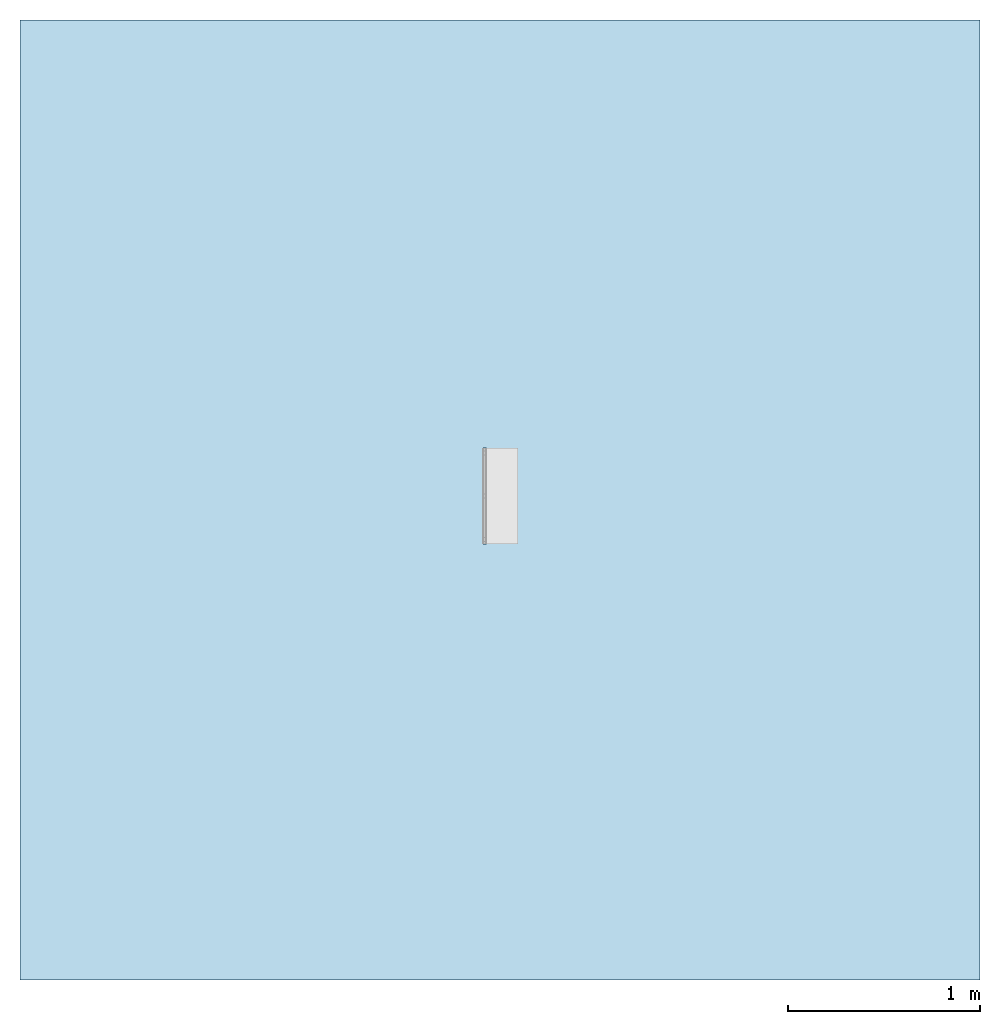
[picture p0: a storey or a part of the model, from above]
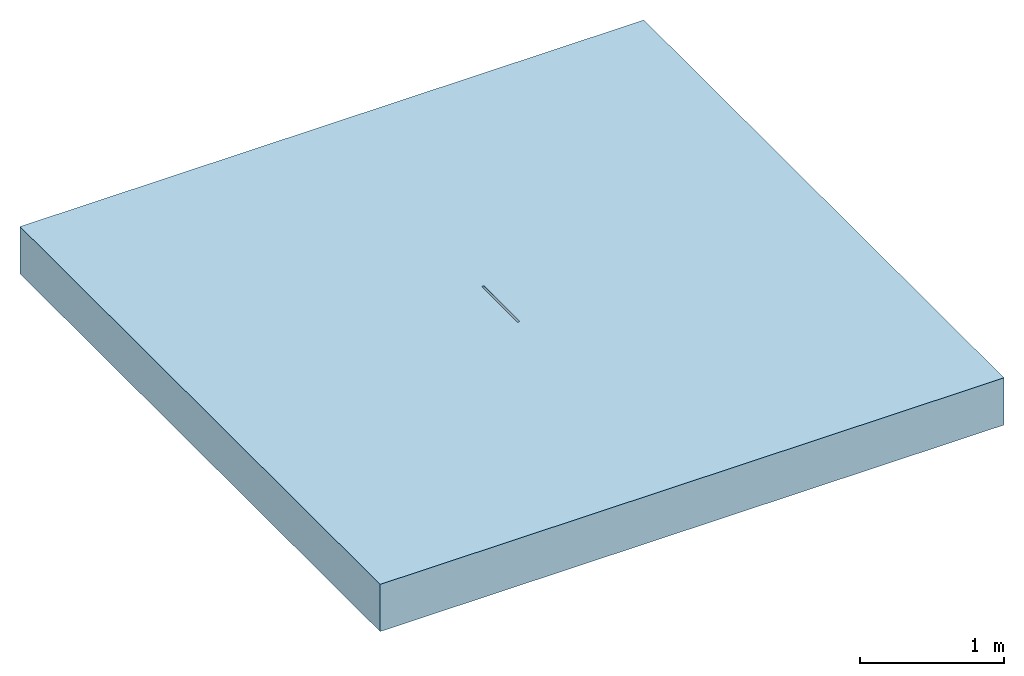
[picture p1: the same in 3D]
Properties of the parts of a building model (IFC2X3)

# File
Description: ViewDefinition [CoordinationView]
File name: 23153 - No 0.1J Constant Depth Channel - 500mm LG - Invert Depth 185mm.ifc
Time: 2013-10-30T12:23:05
Written by: Autodesk Revit 2013
Made in: 20120221_2030(x64)

# IfcProject, Project Number
LongName: Project Name; Phase: Project Status

# IfcSite, Default
RefLatitude: 42, 21, 30, 344238; RefLongitude: -71, -3, -35, -194702; RefElevation: 0 mm

# IfcBuilding
Pset_BuildingCommon - NumberOfStoreys: 1
Other - Project Address: ## Street City, State Zip; Project Issue Date: Issue Date; Project Name: Project Name; Project Number: Project Number; Client Name: Owner; Project Status: Project Status

# IfcBuildingStorey, Level 1
LongName: Level 1; Elevation: 0 mm
Constraints - Elevation Base: 0; Elevation: 0 mm
Graphics - Color: 0; Symbol at End 2 Default: yes; Line Pattern: Center; Symbol at End 1 Default: no; Line Weight: 1; Symbol: M_Level Head - Circle: M_Level Head - Circle
Identity Data - Name: Level 1; Structural: no; Building Story: yes
Dimensions - Computation Height: 0 mm

# IfcBuildingElementProxy: 23153 - No 0.1J Constant Depth Channel - 500mm LG - Invert Depth 185mm, Civil-Drainage-Channel-ACO-MultiDrain-M150D-Brickslot-Channel-System:23153 - No 0.1J Constant Depth Channel - 500mm LG - Invert Depth 185mm:23153 - No 0.1J Constant Depth Channel - 500mm LG - Invert Depth 185mm:196059
In: Level 1
Material: Steel, Galvanized, Vienite® Synthetic Resin Concrete
Dimensions - EndCap Position: 500 mm; FloorCut_Length: -500 mm; Custom_Void_Length: 0 mm; Volume: 6289628 mm3; Brickslot Access Unit Void Depth: -6000 mm; Length: 1000 mm; Brickslot Grating Void Depth: 0 mm; Brickslot Void Length: -500 mm; Brickslot Access Unit Void Bottom Depth: -6105 mm; Floor cut gap depth for access unit: 105 mm; EndCap_Height: -210 mm; Length Drain: -500 mm; Depth: 210 mm; InvDepth: 110 mm; End Cap Thickess: 3 mm; Floor Cut Gap: 105 mm; FloorCut_Width: 185 mm; FloorCut_HorPosition: 92.5 mm; FloorCut_Depth: 210 mm
Constraints - Level: Level: Level 1; Moves With Nearby Elements: no
Construction - 23159_Universal Endcap (Male End): no; 23175_Load Class C250 & D400_Brickslot Grating_Galvanized Steel_1000mm Long: no; 23159_Universal Endcap (Female End): no; 23177_Load Class C250 & D400_Brickslot_Access Unit_Galvanized Steel_500mm Long: no; 23176_Load Class C250 & D400_Brickslot Grating_Galvanized Steel_500mm Long: yes; Constant Depth Channel_1000: no; 23157_Shallow Depth Channel with seal: no; Constant Depth Channel_500: yes; Sump Unit: no; 23156_Shallow Depth Channel: no
Phasing - Phase Created: New Construction
Pset_BuildingElementProxyCommon - Reference: 23153 - No 0.1J Constant Depth Channel - 500mm LG - Invert Depth 185mm
Identity Data - Product Code: 23153; Address: ACO Business Park, Hitchin Road, Shefford, Bedfordshire, United Kingdom SG17 5TE; Manufacturer: ACO Technologies plc - ACO Water Management Division; Watermark 2: This file is water marked and users are prohibited to reproduce, adapt, distribute this information; Price: POA - contact ACO; Type Comments: ACO MultiDrain M150D 0.1J Constant Depth Channel 500mm Long; Product brochure: http://www.aco.co.uk/download.php?id=173; Assembly Code: D2040; e-mail Sales: customersupport@aco.co.uk; Assembly Description: Rain Water Drainage; OmniClass Title: Rainwater Removal; Model: ACO MultiDrain MD Brickslot - M150D; Fax: +44 (0)1462 815895; URL: www.aco.co.uk; Watermark 1: This file is the property of ACO Technologies PLC; Cost: 0; e-mail Technical: technical@aco.co.uk; Product Page URL: http://www.aco.co.uk/product_detail.php?id=58; Maintenance guidelines: http://www.aco.co.uk/download.php?id=173; OmniClass Number: 23.70.50.24; Telephone: +44 (0)1462 816666; Watermarked With: BIM Manager Premium Suite; Model Description: Channel drainage system; Watermarked By: www.aco.co.uk; Installation guidelines: http://www.aco.co.uk/download.php?id=173
General - SerialNumber: 0; TagNumber: 0
Materials and Finishes - Edge Rail Finish: Pre-galvanised; Channel Material: Vienite® Synthetic Resin Concrete; Edge Rail Colour: Silver; Edge Rail Material: Steel; Channel Colour: Brown
Green Building Properties - Channel Recycled Material Content: 20% minimum; Channel Recyclable: Fully recyclable; Edge Rail Recycled Material Content: Between 40% - 90%; Edge Rail Recyclable: Fully recyclable
Model Properties - End Cap Product code 23159: No. 306 Universal End Cap - 185mm wide x 310mm long - Spigot Ø110mm x 50mm long - Silver - Co-Polymer Polypropylene - 0.3kg; Brickslot Grating Product code 23175: N/A; Brickslot Grating Product code 23176: Load Class C250/D400 -Brickslot Galvanized Steel - 500mm long x 105mm high - 10mm Slot - Intake area 10000mm²/m - 3.8kg; Brickslot Access Unit Product code 23177: Load Class C250/D400 - Brickslot Access Unit Galvanised steel - 500mm long x 105mm high - 10mm Slot -Intake area 10000mm²/m - 7.0kg
Data - Concrete Surround Volume - Load Class A 15 - Concrete Pavement: 0.09m³/m; Concrete Surround Volume - Load Class B 125 - C 250 - Concrete Pavement: 0.14m³/m; Product Standard: BS EN 1433:2002, CE marked; Channel C.S.A: 0.020m²; Concrete Surround Volume - Load Class D 400 - Concrete Pavement: 0.21m³/m; Invert Depth: 185mm; ACO Hydraulic Design Software: http://www.acodesign.co.uk; Product Weight: 12.7Kg; Installation - Concrete Grade: Refer to brochure; Pre-formed Outlet Ø: N/A; Product Dimensions: 500mm x 185mm x 210mm (LxWxH); Load Class: A 15 - D 400; Hydraulic Performance: http://www.aco.co.uk/download.php?id=173
Other - Revision: 1; CreatedBy: www.aco.co.uk

# IfcOpeningElement: Recess (2)
In: Level 1
Dimensions - Thickness: 400 mm; Perimeter: 20000 mm; Area: 25000000 mm2; Volume: 9979630000 mm3
Phasing - Phase Created: New Construction
Structural - Structural: no; Enable Analytical Model: no
Constraints - Related to Mass: no; Room Bounding: yes; Level: Level: Level 1; Height Offset From Level: 0 mm
Analytical Properties - Roughness: 1; Heat Transfer Coefficient (U): 2.0925; Absorptance: 0.1; Thermal mass: 543920; Thermal Resistance (R): 0.477897
Materials and Finishes - Structural Material: Earth
Construction - Function: 0; Default Thickness: 400 mm
Graphics - Coarse Scale Fill Color: 0

# IfcSlab: Floor:Generic Floor - 400mm, Floor:Generic Floor - 400mm:193825
In: Level 1
PredefinedType: FLOOR; Material: Earth 400 mm
Dimensions - Thickness: 400 mm; Perimeter: 20000 mm; Area: 25000000 mm2; Volume: 9979630000 mm3
Phasing - Phase Created: New Construction
Structural - Structural: no; Enable Analytical Model: no
Constraints - Related to Mass: no; Room Bounding: yes; Level: Level: Level 1; Height Offset From Level: 0 mm
Pset_SlabCommon - Reference: Generic Floor - 400mm; IsExternal: no; LoadBearing: yes
Analytical Properties - Roughness: 1; Heat Transfer Coefficient (U): 2.0925; Absorptance: 0.1; Thermal mass: 543920; Thermal Resistance (R): 0.477897
Materials and Finishes - Structural Material: Earth
Construction - Function: 0; Default Thickness: 400 mm
Graphics - Coarse Scale Fill Color: 0
